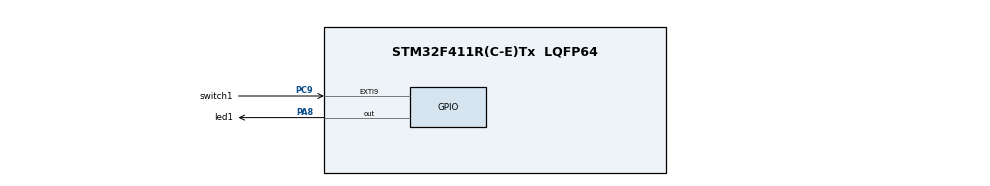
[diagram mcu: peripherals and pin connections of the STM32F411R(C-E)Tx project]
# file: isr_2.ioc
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Mcu.Family=STM32F4
Mcu.Name=STM32F411R(C-E)Tx
Mcu.Package=LQFP64
NVIC.PriorityGroup=NVIC_PRIORITYGROUP_0
PA8.GPIO_Label=led1
PA8.Signal=GPIO_Output
PC9.GPIO_Label=switch1
PC9.GPIO_ModeDefaultEXTI=GPIO_MODE_IT_RISING_FALLING
PC9.GPIO_PuPd=GPIO_PULLUP
PC9.Signal=GPXTI9
PH0\ -\ OSC_IN.Mode=HSE-External-Clock-Source
PH0\ -\ OSC_IN.Signal=RCC_OSC_IN
PH1\ -\ OSC_OUT.Mode=HSE-External-Clock-Source
PH1\ -\ OSC_OUT.Signal=RCC_OSC_OUT
ProjectManager.HeapSize=0x200
ProjectManager.StackSize=0x400
ProjectManager.TargetToolchain=STM32CubeIDE
RCC.48MHZClocksFreq_Value=84000000
RCC.AHBFreq_Value=84000000
RCC.APB1CLKDivider=RCC_HCLK_DIV2
RCC.APB1Freq_Value=42000000
RCC.APB1TimFreq_Value=84000000
RCC.APB2Freq_Value=84000000
RCC.APB2TimFreq_Value=84000000
RCC.CortexFreq_Value=84000000
RCC.FLatency-AdvancedSettings=FLASH_LATENCY_2
RCC.HCLKFreq_Value=84000000
RCC.HSE_VALUE=8000000
RCC.HSI_VALUE=16000000
RCC.PLLN=336
RCC.PLLP=RCC_PLLP_DIV4
RCC.SYSCLKFreq_VALUE=84000000
RCC.SYSCLKSource=RCC_SYSCLKSOURCE_PLLCLK
RCC.VCOOutputFreq_Value=336000000
board=NUCLEO-F411RE

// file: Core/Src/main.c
/* USER CODE BEGIN Header */
/**
  ******************************************************************************
  * @file           : main.c
  * @brief          : Main program body
  ******************************************************************************
  * @attention
  *
  * Copyright (c) 2024 STMicroelectronics.
  * All rights reserved.
  *
  * This software is licensed under terms that can be found in the LICENSE file
  * in the root directory of this software component.
  * If no LICENSE file comes with this software, it is provided AS-IS.
  *
  ******************************************************************************
  */
/* USER CODE END Header */
#include "main.h"

/* USER CODE BEGIN PD */
#define DEBOUNCE_DELAY 50    // Debounce delay for button press
/* USER CODE END PD */

/* USER CODE BEGIN PV */
static uint8_t led_state = 0; // LED state tracker
/* USER CODE END PV */

void SystemClock_Config(void);
static void MX_GPIO_Init(void);
void Error_Handler(void);

int main(void)
{

  /* MCU Configuration--------------------------------------------------------*/

  /* Reset of all peripherals, Initializes the Flash interface and the Systick. */
  HAL_Init();

  /* Configure the system clock */
  SystemClock_Config();

  /* Initialize all configured peripherals */
  MX_GPIO_Init();

  /* Infinite loop */
  while (1)
  {

    /* USER CODE BEGIN 3 */
    // Nothing needed in main loop, LED toggling handled in interrupt
  }
  /* USER CODE END 3 */
}

static void MX_GPIO_Init(void)
{
  GPIO_InitTypeDef GPIO_InitStruct = {0};

  /* GPIO Ports Clock Enable */
  __HAL_RCC_GPIOC_CLK_ENABLE();
  __HAL_RCC_GPIOH_CLK_ENABLE();
  __HAL_RCC_GPIOA_CLK_ENABLE();
  __HAL_RCC_GPIOB_CLK_ENABLE();
  __HAL_RCC_SYSCFG_CLK_ENABLE(); // Enable SYSCFG clock for external interrupts

  /*Configure GPIO pin Output Level */
  HAL_GPIO_WritePin(GPIOA, led1_Pin, GPIO_PIN_RESET);

  /*Configure GPIO pin : switch1_Pin */
  GPIO_InitStruct.Pin = switch1_Pin;
  GPIO_InitStruct.Mode = GPIO_MODE_IT_FALLING;  // Detect only button press
  GPIO_InitStruct.Pull = GPIO_PULLUP;
  HAL_GPIO_Init(switch1_GPIO_Port, &GPIO_InitStruct);

  /*Configure GPIO pin : led1_Pin */
  GPIO_InitStruct.Pin = led1_Pin;
  GPIO_InitStruct.Mode = GPIO_MODE_OUTPUT_PP;
  GPIO_InitStruct.Pull = GPIO_NOPULL;
  GPIO_InitStruct.Speed = GPIO_SPEED_FREQ_LOW;
  HAL_GPIO_Init(GPIOA, &GPIO_InitStruct);

  /* EXTI interrupt init*/
  HAL_NVIC_SetPriority(EXTI9_5_IRQn, 0, 0);
  HAL_NVIC_EnableIRQ(EXTI9_5_IRQn);
}

/* USER CODE BEGIN 4 */
void HAL_GPIO_EXTI_Callback(uint16_t GPIO_Pin)
{
  if (GPIO_Pin == switch1_Pin)
  {
    HAL_Delay(DEBOUNCE_DELAY);  // Debounce delay
    if (HAL_GPIO_ReadPin(switch1_GPIO_Port, switch1_Pin) == GPIO_PIN_RESET) // Confirm button press
    {
      led_state = !led_state; // Toggle LED state
      HAL_GPIO_WritePin(GPIOA, led1_Pin, led_state ? GPIO_PIN_SET : GPIO_PIN_RESET);
    }
  }
}

/**
  * @brief This function is executed in case of error occurrence.
  * @retval None
  */
void Error_Handler(void)
{
  while (1)
  {
    // Stay here in case of error
  }
}
/* USER CODE END 4 */
void SystemClock_Config(void)
{
  RCC_OscInitTypeDef RCC_OscInitStruct = {0};
  RCC_ClkInitTypeDef RCC_ClkInitStruct = {0};

  /** Configure the main internal regulator output voltage */
  __HAL_PWR_VOLTAGESCALING_CONFIG(PWR_REGULATOR_VOLTAGE_SCALE1);

  /** Initializes the RCC Oscillators */
  RCC_OscInitStruct.OscillatorType = RCC_OSCILLATORTYPE_HSE;
  RCC_OscInitStruct.HSEState = RCC_HSE_ON;
  RCC_OscInitStruct.PLL.PLLState = RCC_PLL_ON;
  RCC_OscInitStruct.PLL.PLLSource = RCC_PLLSOURCE_HSE;
  RCC_OscInitStruct.PLL.PLLM = 8;
  RCC_OscInitStruct.PLL.PLLN = 336;
  RCC_OscInitStruct.PLL.PLLP = RCC_PLLP_DIV2;
  RCC_OscInitStruct.PLL.PLLQ = 7;

  if (HAL_RCC_OscConfig(&RCC_OscInitStruct) != HAL_OK)
  {
    Error_Handler();
  }

  /** Initializes the CPU, AHB, and APB buses clocks */
  RCC_ClkInitStruct.ClockType = (RCC_CLOCKTYPE_HCLK | RCC_CLOCKTYPE_SYSCLK | RCC_CLOCKTYPE_PCLK1 | RCC_CLOCKTYPE_PCLK2);
  RCC_ClkInitStruct.SYSCLKSource = RCC_SYSCLKSOURCE_PLLCLK;
  RCC_ClkInitStruct.AHBCLKDivider = RCC_SYSCLK_DIV1;
  RCC_ClkInitStruct.APB1CLKDivider = RCC_HCLK_DIV4;
  RCC_ClkInitStruct.APB2CLKDivider = RCC_HCLK_DIV2;

  if (HAL_RCC_ClockConfig(&RCC_ClkInitStruct, FLASH_LATENCY_5) != HAL_OK)
  {
    Error_Handler();
  }
}
